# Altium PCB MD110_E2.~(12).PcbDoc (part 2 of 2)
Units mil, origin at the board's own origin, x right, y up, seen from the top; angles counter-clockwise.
Board outline 2320.49 x 1909 mil, 4 copper layers (Top Layer, Signal Layer 1, Signal Layer 2, Bottom Layer), stack 61.2 mil thick; 89 components, 32 nets, 187 pads, 40 vias.
Unrouted connection lines stored in the file: 7.

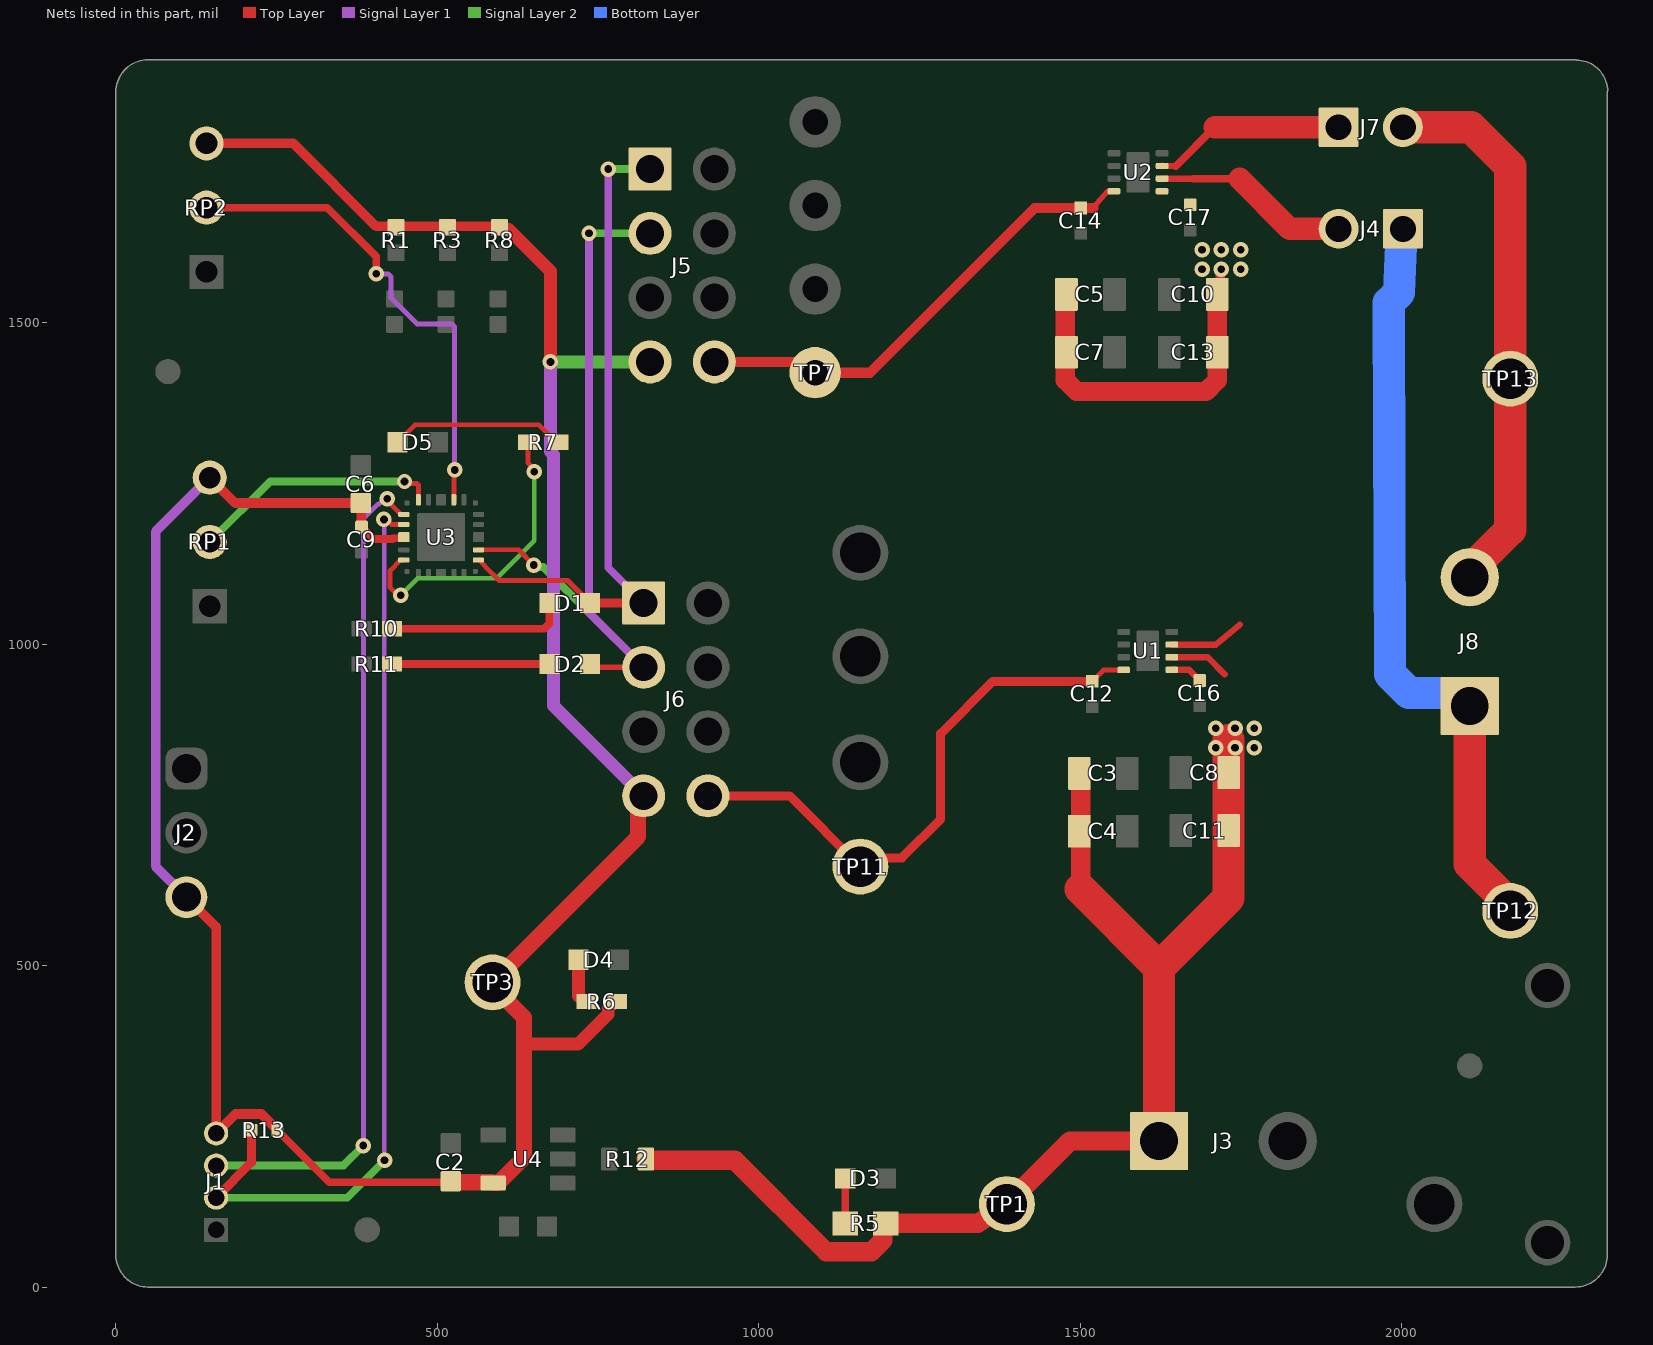
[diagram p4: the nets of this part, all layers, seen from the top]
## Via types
v1: diameter 24, hole 12, Top Layer to Bottom Layer, tented both sides, 36 vias
v2: diameter 19.68, hole 7.87, Top Layer to Bottom Layer, tented both sides, 4 vias

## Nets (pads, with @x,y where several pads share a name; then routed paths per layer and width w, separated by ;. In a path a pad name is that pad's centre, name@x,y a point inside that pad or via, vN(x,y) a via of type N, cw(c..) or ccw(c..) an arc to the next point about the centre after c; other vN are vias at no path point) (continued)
NetD1_1: D1.1 R10.1 | length 279.9
  Top Layer w12: R10.1@429.62,1024 666,1024 674.5,1032.5 D1.1@674.5,1064
NetD2_1: D2.1 R11.1 | length 244.9
  Top Layer w12: R11.1@429.62,969 D2.1@674.5,969
NetD3_2: D3.2 R5.2 | length 70
  Top Layer w12: R5.2@1134.5,99 D3.2@1134.5,169
NetD4_2: D4.2 R6.2 | length 72.6
  Top Layer w20: D4.2@719.5,509 719.5,452.94 728.44,444 R6.2@732.38,444
NetD5_2: D5.2 R7.2 | length 273.3
  Top Layer w7.5: D5.2@438.01,1314 465.38,1341.37 657.63,1341.37 676.25,1322.75 676.25,1322.06 684.31,1314 R7.2@688.24,1314
OUT1: J4.1 J8.1 TP12.1 U1.2 | length 1273.9
  Top Layer w10: U1.2@1642.4,979.65 1698.35,979.65 1724.61,953.39
  Top Layer w50: J8.1@2106,904 2106,658.01 2169,595.01 TP12.1@2169,585
  Bottom Layer w50: J4.1@2000,1638 1996.09,1547.09 1980,1531 1982,953.57 2011.29,924.28 2085.72,924.28 J8.1@2106,904
OUT1_B: J4.2 U2.2 | length 306.9
  Top Layer w10: U2.2@1627.4,1724.16 1676,1724
  Top Layer w12: 1676,1724 1748,1724
  Top Layer w35: 1748,1724 1826,1646 J4.2@1902,1646
OUT2: J7.2 J8.2 TP13.1 U1.3 | length 974.1
  Top Layer w10: U1.3@1642.4,999.34 1711.17,999.34 1748,1030
  Top Layer w50: J7.2@2002,1804 2108,1804 2169,1743 TP13.1@2169,1413 2169,1177.97 2106,1114.97 J8.2@2106,1104
OUT2_B: J7.1 U2.3 | length 299.6
  Top Layer w10: U2.3@1627.4,1743.84 1648.68,1743.69
  Top Layer w12: 1648.68,1743.69 1709,1804
  Top Layer w35: 1709,1804 J7.1@1902,1804
PWM1: D1.2 J5.1 J6.1 U3.13 | length 1050.3
  Top Layer w7.5: U3.13@564.07,1130.97 568.99,1130.97 569.18,1130.78 569.18,1126.38 574.71,1120.85 574.71,1120.33 596.04,1099 702.5,1099
  Top Layer w8: 702.5,1099 D1.2@737.5,1064
  Top Layer w14: D1.2@737.5,1064 J6.1@821,1064
  Signal Layer 1 w12: v1(766,1739) 766,1119 J6.1@821,1064
  Signal Layer 2 w12: v1(766,1739) J5.1@831,1739
PWM2: D2.2 J5.3 J6.3 U3.14 | length 1223.4
  Top Layer w7.5: U3.14@564.07,1146.72 626.28,1146.72 v1(650,1123)
  Top Layer w8: D2.2@737.5,969 742.5,964 J6.3@821,964
  Signal Layer 1 w12: v1(736,1639) 736,1049 J6.3@821,964
  Signal Layer 2 w12: v1(650,1123) 652.94,1120.06 664.94,1120.06 J6.3@821,964 ; v1(736,1639) J5.3@831,1639
SBWTCK: J1.3 U3.1 | length 1304.7
  Top Layer w7.5: v1(422,1226) 422,1222.84 443.01,1201.83 U3.1@447.93,1201.83
  Signal Layer 1 w7.5: v1(385,220) 385,1195.41 407.21,1217.62 409.16,1217.62 417.54,1226 v1(422,1226)
  Signal Layer 2 w12: J1.3@156,189 354,189 v1(385,220)
SBWTDIO: J1.2 R13.2 U3.2 | length 1445.4
  Top Layer w7.5: v1(417,1194) 421.1,1194 429.02,1186.09 U3.2@447.93,1186.09
  Top Layer w14: J1.2@156,139 210.82,193.82 R13.2@210.82,244
  Signal Layer 1 w7.5: v1(417,1194) 417.5,1193.5 417.5,197.5 v1(418,197)
  Signal Layer 2 w12: J1.2@156,139 360,139 v1(418,197)
SPD_REF_1: RP2.2 U3.20 | length 767.6
  Top Layer w7.5: U3.20@525.69,1224.47 525.87,1224.66 525.87,1269.87 v1(527,1271)
  Top Layer w12: RP2.2@141,1679 329,1679 405,1603 v1(405,1576)
  Signal Layer 1 w7.5: v1(405,1576) 423.61,1576 428,1571.61 428,1538.59 468.59,1498 522.61,1498 527,1493.61 v1(527,1271)
SPD_REF_2: RP1.2 U3.23 | length 388.8
  Top Layer w7.5: v1(449,1253) 452.16,1249.84 468.29,1249.84 470.57,1247.57 U3.23@470.57,1224.47
  Signal Layer 2 w12: RP1.2@146,1159 240,1253 v1(449,1253)
STATUS: R7.1 U3.5 | length 476.4
  Top Layer w7.5: v1(443,1076) 438.54,1076 426.54,1088 426.54,1114.5 443.01,1130.97 U3.5@447.93,1130.97 ; R7.1@641,1314 641,1282.34 650.87,1272.46 v1(650.87,1268)
  Signal Layer 2 w7.5: v1(443,1076) 469.62,1102.62 592.69,1102.62 650.87,1160.81 v1(650.87,1268)
VCC: C2.2 C6.2 C9.2 J1.4 J2.3 J5.7 J6.7 R1.2 R3.2 R6.1 R8.2 R13.1 RP1.3 RP2.3 TP3.1 U3.3 U4.5 | length 4508
  Top Layer w12: R13.1@251.18,243.51 254.53,240.16 255.02,240.16 332.14,163.04 C2.2@522.44,163.04 ; C9.2@386.06,1178.38 400.78,1163.65 430.24,1163.65 431.12,1164.53 446.06,1164.53 U3.3@447.93,1166.4
  Top Layer w15: J2.3@109.76,606.48 156,560.24 J1.4@156,239 186.22,269.22 226.45,269.22 251.18,244.49 R13.1@251.18,244 R13.1@251.18,243.51 ; RP2.3@141,1779 276,1779 405,1650 R8.2@593,1650 ; RP1.3@146,1259 185.53,1219.47 C6.2@381,1219.47 381.61,1218.86 381.61,1182.83 C9.2@382.22,1182.22
  Top Layer w20: R8.2@596,1649 599.69,1645.31 610.86,1645.31 676,1580.17 v1(676,1439) ; 635,377.83 719.05,377.83 766,424.79 766,434.32 775.68,444 R6.1@779.62,444
  Top Layer w25: C2.2@522.44,163.04 585.43,163.04 U4.5@586.87,161.6 594.74,161.6 635,201.86 635,377.83 635,419.06 586,468.06 TP3.1@586,474 812.54,700.54 812.54,755.54 J6.7@821,764
  Signal Layer 1 w15: J2.3@109.76,606.48 61.91,654.33 61.91,1174.91 RP1.3@146,1259
  Signal Layer 1 w20: v1(676,1439) 676,1299.44 680.75,1294.69 680.75,904.25 J6.7@821,764
  Signal Layer 2 w20: v1(676,1439) J5.7@831,1439
VCC_DRV: C12.2 J6.8 TP11.1 U1.8 | length 896.8
  Top Layer w8: C12.2@1519,942.18 1536.79,959.97 U1.8@1567.6,959.97
  Top Layer w14: J6.8@921,764 1048,764 TP11.1@1158,654 1171.5,667.5 1222.5,667.5 1283,728 1283,861 1364.18,942.18 C12.2@1519,942.18
VCC_DRV_B: C14.2 J5.8 TP7.1 U2.8 | length 736.7
  Top Layer w8: 1520.33,1678.45 U2.8@1542.76,1704.47
  Top Layer w16: J5.8@931,1439 1057.47,1439 1074.19,1422.28 TP7.1@1087.72,1422.28 1173.04,1422.28 1429.2,1678.45 C14.2@1501,1678.45 1520.33,1678.45
VM: C3.1 C4.1 C5.1 C7.1 C8.1 C10.1 C11.1 C13.1 C16.2 C17.2 J3.1 R5.1 R12.1 TP1.1 U1.1 U2.1 | length 2602.6
  Top Layer w10: U1.1@1642.4,959.97 1669.4,959.97 C16.2@1686,943.37 1686,942.16 1690.84,937.32 1690.84,938.53 C16.2@1686.61,942.76
  Top Layer w15: C10.1@1713.4,1544 1717.88,1548.47 1717.88,1581.62 v1(1719.6,1583.35)
  Top Layer w30: R12.1@824.54,199 826.54,197 963,197 1105,55 1175.24,55 1192.81,72.57 1192.81,95.3 1196.51,99 R5.1@1197.5,99 1340.58,99 TP1.1@1386,129 ; TP1.1@1370.58,129 TP1.1@1386,129 ; C5.1@1478.6,1544 1477,1542.4 1477,1410.57 1494.57,1393 1695.83,1393 1713.4,1410.57 C13.1@1713.4,1454 C10.1@1713.4,1544 ; C3.1@1498.6,799 1501,796.6 1501,619 ; J3.1@1622.81,227.11 1484.11,227.11 TP1.1@1386,129
  Top Layer w50: 1501,619 1622.81,497.19 ; J3.1@1622.81,227.11 1622.81,497.19 ; 1731,851 1731,605.38 1622.81,497.19
  other v1: 1711,839 1741,839 1771,839 1711,869 1741,869 1771,869 1689.6,1583.35 1749.6,1583.35 1689.6,1613.35 1719.6,1613.35 1749.6,1613.35
pads on no net: C14.1 FID1.1 FID2.1 FID3.1 H1.0 H2.0 H3.0 H4.0 SH-J1.0 SH-J2.0 SH-J3.0 SH-J4.0 SH-J5.0 SH-J6.0 SH-J7.0 SH-J8.0 SH-J9.0 SH-J10.0 SH-J11.0 U3. U3.6 U3.7 U3.8 U3.9 U3.10 U3.12 U3.18 U3.19 U3.21 U3.22 U3.24 U4.2

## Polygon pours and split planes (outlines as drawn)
VM on Top Layer "TOP_LAYER_VM_P029" (solid, remove dead copper, pour order 29): 1611.6,1699.35 1611.6,1710 1676.94,1710 1769.6,1617.35 1769.6,1567.35 1683.6,1567.35 1674.6,1576.35 1674.6,1665.35 1645.6,1665.35
VM on Top Layer "TOP_LAYER_VM_P024" (solid, remove dead copper, pour order 24): 1633,955 1633,968 1696,968 1791,873 1791,823 1705,823 1696,832 1696,921 1683,921 1649,955
OUT2 on Top Layer "TOP_LAYER_OUT2_P022" (solid, pour order 22): 2303.5,989.5 2303.5,1256.1 1957,1256.1 1667.75,989.5
OUT1 on Top Layer "TOP_LAYER_OUT1_P021" (solid, pour order 21): 1681.36,987.5 2305,987.5 2305,726.5 1969.91,726.5
GND on Top Layer "TOP_LAYER_GND_P056" (solid, remove dead copper, pour order 30): 1,1909 2321.51,1909 2321.51,-81 1,-81
VM on Bottom Layer "BOTTOM_LAYER_VM_P026" (solid, remove dead copper, pour order 26): 1691,819 1791,819 1791,1619 1781,1629 1671,1629 1671,1569 1691,1549
GND on Bottom Layer "BOTTOM_LAYER_GND_P031" (solid, remove dead copper, pour order 31): 1,1 2321.51,1 2321.51,1909 1,1909
GND on Signal Layer 1 "TOP_LAYER_GND_P056" (solid, remove dead copper, pour order 27): 6.76,1918.32 2327.27,1918.32 2327.27,-71.68 6.76,-71.68
GND on Signal Layer 2 "TOP_LAYER_GND_P056" (solid, remove dead copper, pour order 28): 1,1909 2321.51,1909 2321.51,-81 1,-81

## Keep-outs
Keep-Out Layer:
  text ".Layer_Name" at 574,-1780.49 h25

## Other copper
Top Layer:
  text ".Layer_Name" at 574,-1780.49 h25
Bottom Layer:
  text ".Layer_Name" at 574,-1780.49 h25

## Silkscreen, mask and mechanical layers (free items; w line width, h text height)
Top Overlay:
  circle w10: c426,1249 r5
  lines w8: 24.97,44 326,44 326,279 24.97,279 24.97,44 ; 41,394 446,394 446,914 41,914 41,394 ; 41.2,394.45 446.2,394.45 446.2,554.45 41.2,554.45 41.2,394.45 ; 391.95,1436.85 641.95,1436.85 641.95,1716.85 391.95,1716.85 391.95,1436.85 ; 481,54 856,54 856,314.94 481,314.94 481,54 ; 749.99,1329 2081,1329 2081,1879 749.99,1879 749.99,1329
  lines w10: 1481,874.31 1481,1064.05 1709.27,1062.61 1709.72,873.56 1481,874.31
  lines w15: 908.34,359 1461,359 1461,519 908.34,519 908.34,359
  text "IN1/EN PWM" at 245.21,1852.67 h65 r270
  text "OUT2_B" at 1679,1826.31 h45
  text "OUT2" at 2088,1825.61 h45
  text "Parallel / DRV8218" at 753.21,1799.58 h48
  text "IN1/EN" at 1169.72,1794.67 h55
  text "EVM ID / Resistors" at 389.16,1717.81 h48
  text "IN2/PH" at 1169.72,1669.67 h55
  text "OUT1_B" at 1680,1669.31 h45
  text "OUT1" at 2088,1665.52 h45
  text "ID1" at 408.25,1560.94 h40
  text "ID2" at 491.24,1560.94 h40
  text "ID3" at 572.12,1560.94 h40
  text "MODE" at 1169.72,1534.67 h55
  text "VCC" at 1169.72,1404.65 h55
  text "MCU Status" at 418.62,1354.8 h60
  text "IN2/PH PWM" at 260.21,1332.67 h65 r270
  text "OUT2" at 2079.94,1271.4 h80
  text "IN1/EN" at 1240,1118.21 h65
  text "DRV8218DSG" at 1430.12,1074.8 h60
  text "IN2/PH" at 1240,960.21 h65
  text "MODE" at 1240,794.21 h65
  text "GND" at 177.76,792.28 h60
  text "MODE" at 179.76,680.88 h80
  text "OUT1" at 2078.98,662.4 h80
  text "VCC" at 1240,632.18 h65
  text "VCC" at 174.51,587.25 h60
  text "VCC" at 517.33,558.36 h80
  text "VCC LED" at 704.56,544.77 h60
  text "1.8V - 11V" at 1616,544.05 h50
  text "VM" at 1549.94,473.4 h80
  text "GND" at 1744.6,469.41 h80
  text "GND = PWM / VCC = PH/EN / Hi-Z  = ½ bridge" at 56,392.88 h60
  text "Max VCC: 3.3V" at 488.24,364.8 h60
  text "DRV8218EVM" at 911,359.37 h115
  text "3.3V LDO" at 479.72,318.06 h48
  text "'.PRJ_Number'.PCB_Rev" at 904.48,290.98 h72.83
  text "Programming" at 24.72,279.11 h48
  text "VM" at 1334.94,213.4 h80
  text "GND" at 1980,213.4 h80
  text "VM LED" at 1035.93,204.8 h60
  text "0Ω" at 756.31,111.58 h70
  text ".Layer_Name" at 574,-1780.49 h25
Bottom Overlay:
  text ".Layer_Name" at 574,-1780.49 h25
Top Paste:
  text ".Layer_Name" at 574,-1780.49 h25
Bottom Paste:
  text ".Layer_Name" at 574,-1780.49 h25
Top Solder:
  text ".Layer_Name" at 574,-1780.49 h25
  text ".Layer_Name" at 574,-1780.49 h25
Bottom Solder:
  text ".Layer_Name" at 574,-1780.49 h25
Drill Guide:
  text ".Layer_Name" at 574,-1780.49 h25
M1 Board Outline:
  lines w10: 0,50 ccw(c50,50) 50,0 2270,0 ccw(c2270,50) 2320,50 2320,1860 ; 0,51 0,1859 cw(c50,1859) 50,1909 2272,1909 ; 2270.86,1909 cw(c2270.86,1908.35) 2271.51,1908.35 ; 2272,1908.49 cw(c2272,1860) 2320.49,1860
  text ".Layer_Name" at 574,-1780.49 h25
M2 Board Dimensions:
  rectangle: -3,-1197 122,-1072
  rectangle: 122,-1322 497,-1197
  lines w7: -3,-1197 997,-1197 ; 122,-1322 122,-1072 ; 247,-1322 247,-1072 ; 497,-1322 497,-1072 ; 747,-1322 747,-1072 ; -3,-1322 997,-1322 997,-1072 -3,-1072 -3,-1322
  text ".Layer_Name" at 574,-1780.49 h25
M3 3D STEP Top:
  text ".Layer_Name" at 574,-1780.49 h25
M4 3D STEP Bottom:
  text ".Layer_Name" at 574,-1780.49 h25
M5 Assembly Top:
  lines w10: -295,-1852.17 6305,-1852.17 ; -295,-1648.83 6307,-1648.83 ; -295,-1445.5 -295,-2055.5 3710,-2055.5 6307,-2055.5 6307,-1445.5 -294.5,-1445.5 -294.5,-2055.5 1281,-2055.5 ; 2170,-2055.5 2170,-1445.5 ; 3437,-1648.83 3437,-1445.5 ; 4277,-1648.83 4277,-1445.5 ; 4899,-2062 4899,-1859.17
  text "COMPONENTS MARKED 'DNP' SHOULD NOT BE POPULATED." at 1150.5,-1240.5 h25
  text "ASSEMBLY VARIANT:" at 1150,-1356 h25
  text ".VariantName" at 2186,-1356 h25
  text "PCB VIEWED FROM TOP SIDE" at -231.5,-1577.67 h25
  text "BOARD #:" at 2245,-1577.67 h25
  text ".PRJ_Number" at 2790.5,-1577.67 h25
  text "REV:" at 3635,-1577.67 h25
  text ".PCB_Rev" at 3926.5,-1577.67 h25
  text "SVN REV:" at 4473,-1577.67 h25
  text ".VersionControl_RevNumber" at 4979,-1577.67 h25
  text "TID #:" at 2245,-1781 h25
  text ".TID" at 2790.5,-1781 h25
  text "PLOT NAME =" at -231.5,-1986.34 h25
  text ".plot_File_Name" at 574,-1986.34 h25
  text "GENERATED    :" at 2247,-1986.34 h25
  text ".Print_Date" at 3116.5,-1986.34 h25
  text ".Print_Time" at 3845.5,-1986.34 h25
  text "TEXAS INSTRUMENTS" at 5110,-1986.34 h25
M6 Assembly Bottom:
  lines w10: -295.5,-1649.33 6306.5,-1649.33 ; -293.5,-1852.67 6306.5,-1852.67 ; 1112.5,-2062.5 1112.5,-1859.67 ; 1734.5,-1649.33 1734.5,-1446 ; 2574.5,-1649.33 2574.5,-1446 ; 3841.5,-2056 3841.5,-1446 ; 4730.5,-2056 6306,-2056 6306,-1446 -295.5,-1446 -295.5,-2056 2301.5,-2056 6306.5,-2056 6306.5,-1446
  text "COMPONENTS MARKED 'DNP' SHOULD NOT BE POPULATED." at 6099,-1240 h25
  text ".VariantName" at 5055,-1356 h25
  text "ASSEMBLY VARIANT:" at 6094,-1356 h25
  text ".VersionControl_RevNumber" at 1032.5,-1578.17 h25
  text "SVN REV:" at 1538.5,-1578.17 h25
  text ".PCB_Rev" at 2085,-1578.17 h25
  text "REV:" at 2376.5,-1578.17 h25
  text ".PRJ_Number" at 3221,-1578.17 h25
  text "BOARD #:" at 3766.5,-1578.17 h25
  text "PCB VIEWED FROM BOTTOM SIDE" at 6243,-1578.17 h25
  text ".TID" at 3221,-1781.5 h25
  text "TID #:" at 3766.5,-1781.5 h25
  text "TEXAS INSTRUMENTS" at 901.5,-1986.84 h25
  text ".Print_Time" at 2166,-1986.84 h25
  text ".Print_Date" at 2895,-1986.84 h25
  text "GENERATED    :" at 3764.5,-1986.84 h25
  text ".plot_File_Name" at 5437.5,-1986.84 h25
  text "PLOT NAME =" at 6243,-1986.84 h25
M9 Title Sheet:
  drawing of 57 lines, arcs and shapes, not listed
  text "1" at 736.84,7114.5 h25
  text "2" at 3232.5,7114.5 h25
  text "3" at 5721.84,7114.5 h25
  text "4" at 8228.51,7114.5 h25
  text "5" at 10727.5,7114.5 h25
  text "6" at 13232.5,7114.5 h25
  text "A" at -419.5,5971.5 h25
  text "A" at 14380.5,5971.5 h25
  text "B" at -419.5,3591.5 h25
  text "B" at 14380.5,3591.5 h25
  text "C" at -419.5,1216.5 h25
  text "C" at 14380.5,1216.5 h25
  text "PROJECT TITLE:" at 11340.5,-644.5 h25
  text ".PRJ_Title" at 11390.5,-777.83 h25
  text "DESIGNED FOR:" at 11340.5,-945.5 h25
  text ".PRJ_Customer" at 11390.5,-1085.5 h25
  text "D" at -419.5,-1153.5 h25
  text "D" at 14380.5,-1153.5 h25
  text "FILE NAME:" at 11340.5,-1245.5 h25
  text ".PCB_File_Name_No_Path" at 11390.5,-1365.5 h25
  text "Texas Instruments (TI) and/or its licensors do not warrant the accuracy or completeness of this specification" at 6371,-1527.34 h25
  text "ENGINEER:" at 11340.5,-1535.5 h25
  text "LAYOUT BY:" at 12845.5,-1535.5 h25
  text "or any information contained therein. TI and/or its licensors do not warrant that this design will meet" at 6326.01,-1640 h25
  text ".PRJ_Engineer" at 11390.5,-1690.49 h25
  text ".PCB_Layout" at 12896,-1690.49 h25
  text "the specifications, will be suitable for your application or fit for any particular purpose, or will operate in" at 6326.01,-1752.67 h25
  text ".Layer_Name" at 574,-1780.49 h25
  text "ALTIUM DESIGNER VERSION:" at 12845.5,-1845.5 h25
  text "an implementation. TI and/or its licensors do not warrant that the design is production worthy. You should" at 6326.01,-1865.33 h25
  text "completely validate and test your design implementation to confirm the system functionality for your application." at 6371,-1978 h25
  text ".print_Scale" at 11390.5,-1978.83 h25
  text ".Application_BuildNumber" at 12896,-1978.83 h25
  text "1" at 736.84,-2185.5 h25
  text "2" at 3232.5,-2185.5 h25
  text "3" at 5721.84,-2185.5 h25
  text "4" at 8228.51,-2185.5 h25
  text "5" at 10727.5,-2185.5 h25
  text "6" at 13232.5,-2185.5 h25
M10 Fab Notes:
  drawing of 189 lines, arcs and shapes, not listed
  text "DESIGN INFORMATION" at 12379.02,5434.17 h25
  text "MIN. TRACK WIDTH:" at 11734.46,5302.05 h25
  text "8" at 12830.7,5302.05 h25
  text "MIL" at 12985.46,5302.05 h25
  text "MIN. CLEARANCE:" at 11734.46,5177.92 h25
  text "0.2" at 12770.7,5177.93 h25
  text "mm" at 12985.46,5177.92 h25
  text "MIN. VIA PAD SIZE:" at 11734.46,5053.8 h25
  text "24" at 12800.71,5053.8 h25
  text "MIL" at 12985.46,5053.8 h25
  text "0.05mm (2MIL)" at 12429.46,4923.9 h25
  text "MINIMUM ANNULAR RING" at 11405.23,4915.67 h25
  text "EXTERNAL" at 13137.46,4915.67 h25
  text "PER" at 11605.23,4805.55 h25
  text "IPC-D-275 CLASS 2 LEVEL C" at 11825.23,4805.54 h25
  text "MIL, HOLES" at 13313.46,4705.07 h25
  text "+/-" at 12921,4696.48 h25
  text "+/-" at 13775,4696.48 h25
  text "REGISTRATION TOLERANCES:" at 11405.23,4695.42 h25
  text "METAL" at 12605,4695.42 h25
  text "5" at 13181.2,4695.42 h25
  text "3" at 14014.2,4695.42 h25
  text "MIL" at 14130.46,4695.42 h25
  text "HOLE SIZE TOLERANCE (UNLESS OTHERWISE SPECIFIED):" at 11405.23,4597.1 h25
  text "+/-" at 13775,4594.23 h25
  text "3" at 14014.2,4593.17 h25
  text "MIL" at 14130.46,4593.17 h25
  text "MATERIAL:" at 11330.46,4455.52 h25
  text "FR-4 High Tg" at 12316.9,4327 h25
  text "X" at 12172.46,4319.01 h25
  text "FR-408" at 11751.46,4314.49 h25
  text "OTHER" at 13239.46,4314.49 h25
  text "62 MIL (1.6mm) +/-10%" at 12071.56,4171.46 h25
  text "X" at 11951.46,4169.01 h25
  text "THICKNESS:" at 11405.23,4163.24 h25
  text "OTHER" at 13356.46,4163.24 h25
  text "TOLERANCE:" at 11405.23,4024.92 h25
  text "X" at 12253.46,4024.92 h25
  text "ANSI IPC-6012 TYPE 3 CLASS 2" at 12431.48,4024.92 h25
  text "OTHER +/-" at 12431.46,3880.73 h25
  text "BOW & TWIST:" at 11405.23,3735.54 h25
  text "X" at 12253.46,3735.54 h25
  text "ANSI IPC-6012 TYPE 3 CLASS 2" at 12431.48,3735.54 h25
  text "OTHER +/-" at 12431.46,3588.85 h25
  text "DRILLING:" at 11330.46,3458.23 h25
  text "NC_DRILL FILES" at 13091.46,3353.04 h25
  text "REFERENCE:" at 11405.23,3349.1 h25
  text "X" at 12062.46,3349.01 h25
  text "AS SHOWN" at 12240.46,3349.1 h25
  text "X" at 12963.46,3349.1 h25
  text "OTHER" at 13389.46,3206.85 h25
  text "PTH COPPER THICKNESS:" at 11404.91,3203.32 h25
  text "X" at 12544.14,3203.32 h25
  text "20-30 um" at 12672.14,3203.32 h25
  text "BOARD FINISH:" at 11330.46,3055.73 h25
  text "SILKSCREEN:" at 11485.68,2945.6 h25
  text "X" at 12443.46,2945.6 h25
  text "TOP" at 12560.46,2945.6 h25
  text "X" at 12953.46,2945.6 h25
  text "BOTTOM" at 13071.46,2945.6 h25
  text "SILKSCREEN COLOR:" at 11485.68,2790.41 h25
  text "X" at 12442.46,2790.41 h25
  text "WHITE" at 12560.46,2790.41 h25
  text "OTHER" at 13071.46,2790.41 h25
  text "X" at 12573.46,2646.96 h25
  text "GREEN" at 12691.46,2646.96 h25
  text "OTHER" at 13309.46,2646.96 h25
  text "SOLDER RESIST COLOR:" at 11485.68,2640.1 h25
  text "X" at 12573.46,2492.71 h25
  text "MATTE" at 12691.46,2492.71 h25
  text "SEMI-GLOSS" at 13309,2492.07 h25
  text "IMMERSION GOLD (ENIG)" at 12391.46,2319.94 h25
  text "ENEPIG" at 13729,2312.72 h25
  text "SURFACE FINISH:" at 11330.46,2311.72 h25
  text "X" at 12213.46,2311.72 h25
  text "IMM. TIN/SILVER OR EQUIV" at 11660,2174.4 h25
  text "OTHER" at 13091.46,2170.47 h25
  text "ARRAY/PANEL:" at 11330.46,2015.09 h25
  text "CUT AND TRIM PER M1 BOARD OUTLINE" at 12391.46,2006.87 h25
  text "N.C. ROUTE" at 12391.46,1870.9 h25
  text "X" at 13079.46,1870.9 h25
  text "V. SCORE" at 13257.46,1870.9 h25
  text "CERTIFICATION:" at 11330.46,1741.77 h25
  text "MATERIALS AND WORKMANSHIP FOR ALL PCBS" at 12055.46,1741.77 h25
  text "TO MEET OR EXCEED THE REQUIREMENTS OF:" at 12055.46,1647.71 h25
  text "X" at 11692.97,1519.08 h25
  text "ANSI IPC-A-600F CLASS ->" at 11820.96,1519.08 h25
  text "X" at 13468.97,1519.08 h25
  text "2" at 13578.96,1519.08 h25
  text "1" at 13263.96,1517.58 h25
  text "3" at 13932.96,1517.58 h25
  text "X" at 12504.97,1371.39 h25
  text "RoHS" at 12632.96,1371.39 h25
  text "OTHER" at 13277.36,1371.39 h25
  text "PER ORDER" at 13674.42,1371.39 h25
  text "ALL BOARDS MUST MEET OR EXCEED UL94-V0 REQUIREMENTS." at 11358,1217.57 h25
  text "PCB MUST BEAR THE UL94V-0 UL REGISTERED MATERIAL ID NUMBER" at 11358,1101.5 h25
  text "ADDITIONAL REQUIREMENTS:" at 11330.46,932.08 h25
  text "MICROSECTION:" at 11405.23,824.95 h25
  text "YES" at 12310.96,824.95 h25
  text "REQUIRED" at 13172.46,680.62 h25
  text "BARE BOARD ELEC. TEST:" at 11405.23,677.76 h25
  text "NONE" at 12710.96,677.76 h25
  text "X" at 13054.46,677.76 h25
  text "PER ORDER" at 13764.46,677.76 h25
  text "XX MIL VIAS REQUIRE NON-CONDUCTIVE FILL AND PLANARIZE" at 11573.38,472.82 h25
  text "XX MIL VIAS REQUIRE CONDUCTIVE FILL AND PLANARIZE" at 11581.38,368.84 h25
  text "OUTER XX MIL TRACES REQUIRE 50 OHM SINGLE-ENDED IMPEDANCE" at 11580.39,205.46 h25
  text "LAYER 2 & 3 (INNER LAYERS) XX MIL WIDE, XX MIL SPACE / TRACES REQUIRE 100 OHM DIFFERENTIAL IMPEDANCE" at 11572.39,-30.26 h25
  text ".Layer_Name" at 574,-1780.49 h25
M11 Gerber Information:
  lines w10: -295,-1852.17 6305,-1852.17 ; -295,-1648.83 6307,-1648.83 ; -295,-1445.5 -295,-2055.5 3710,-2055.5 6307,-2055.5 6307,-1445.5 -294.5,-1445.5 -294.5,-2055.5 1281,-2055.5 ; 2170,-2055.5 2170,-1445.5 ; 3437,-1648.83 3437,-1445.5 ; 4277,-1648.83 4277,-1445.5 ; 4899,-2062 4899,-1859.17
  text "ALL ARTWORK VIEWED FROM TOP SIDE" at -231.5,-1577.67 h25
  text "BOARD #:" at 2245,-1577.67 h25
  text ".PRJ_Number" at 2790.5,-1577.67 h25
  text "REV:" at 3635,-1577.67 h25
  text ".PCB_Rev" at 3926.5,-1577.67 h25
  text "SVN REV:" at 4473,-1577.67 h25
  text ".VersionControl_RevNumber" at 4979,-1577.67 h25
  text "LAYER NAME =" at -231.5,-1780.49 h25
  text "TID #:" at 2245,-1781 h25
  text ".TID" at 2790.5,-1781 h25
  text "PLOT NAME =" at -231.5,-1986.34 h25
  text ".plot_File_Name" at 574,-1986.34 h25
  text "GENERATED    :" at 2247,-1986.34 h25
  text ".Print_Date" at 3116.5,-1986.34 h25
  text ".Print_Time" at 3845.5,-1986.34 h25
  text "TEXAS INSTRUMENTS" at 5110,-1986.34 h25
M12 Stackup:
  drawing of 306 lines, arcs and shapes, not listed
  text "Layer" at 9168.67,1067.5 h25
  text "Name" at 9351.13,1067.5 h25
  text "Material" at 9754.36,1067.5 h25
  text "Thickness" at 10124.26,1067.5 h25
  text "Constant" at 10406.69,1067.5 h25
  text "Board Layer Stack" at 10655.8,1067.5 h25
  text "Top Overlay" at 9351.13,1017.5 h25
  text "Top Solder" at 9351.13,967.5 h25
  text "Solder Resist" at 9754.36,967.5 h25
  text "0.40mil" at 10124.26,967.5 h25
  text "3.5" at 10406.69,967.5 h25
  text "1" at 9168.67,917.5 h25
  text "Top Layer" at 9351.13,917.5 h25
  text "2.80mil" at 10124.26,917.5 h25
  text "Dielectric 1" at 9351.13,867.5 h25
  text "FR4 370" at 9754.36,867.5 h25
  text "11.40mil" at 10124.26,867.5 h25
  text "4.2" at 10406.69,867.5 h25
  text "2" at 9168.67,817.5 h25
  text "Signal Layer 1" at 9351.13,817.5 h25
  text "1.40mil" at 10124.26,817.5 h25
  text "Dielectric 2" at 9351.13,767.5 h25
  text "FR4 370" at 9754.36,767.5 h25
  text "30.00mil" at 10124.26,767.5 h25
  text "4.2" at 10406.69,767.5 h25
  text "3" at 9168.67,717.5 h25
  text "Signal Layer 2" at 9351.13,717.5 h25
  text "1.40mil" at 10124.26,717.5 h25
  text "Dielectric 3" at 9351.13,667.5 h25
  text "FR4 370" at 9754.36,667.5 h25
  text "11.40mil" at 10124.26,667.5 h25
  text "4.2" at 10406.69,667.5 h25
  text "4" at 9168.67,617.5 h25
  text "Bottom Layer" at 9351.13,617.5 h25
  text "2.80mil" at 10124.26,617.5 h25
  text "Bottom Solder" at 9351.13,567.5 h25
  text "Solder Resist" at 9754.36,567.5 h25
  text "0.40mil" at 10124.26,567.5 h25
  text "3.5" at 10406.69,567.5 h25
  text "Bottom Overlay" at 9351.13,517.5 h25
  text ".Layer_Name" at 574,-1780.49 h25
M13 Component Bodies Top:
  text ".Layer_Name" at 574,-1780.49 h25
M14 Component Bodies Bottom:
  text ".Layer_Name" at 574,-1780.49 h25
M15 Courtyards Top:
  text ".Layer_Name" at 574,-1780.49 h25
M16 Courtyards Bottom:
  text ".Layer_Name" at 574,-1780.49 h25
Drill Drawing:
  circle w10: c9771.85,322.66 r6.9
  circle w10: c9771.85,322.66 r11.5
  circle w10: c9771.85,-91.29 r11.5
  lines w10: 9760.36,-200.53 9766.1,-200.53 9766.1,-206.28 9777.6,-206.28 9777.6,-200.53 9783.35,-200.53 9783.35,-189.03 9777.6,-189.03 9777.6,-183.28 9766.1,-183.28 9766.1,-189.03 9760.36,-189.03 9760.36,-200.53 ; 9760.36,-154.54 9760.36,-148.79 9766.1,-143.04 9760.36,-137.29 9760.36,-131.54 9766.1,-131.54 9771.85,-137.29 9777.6,-131.54 9783.35,-131.54 9783.35,-137.29 9777.6,-143.04 9783.35,-148.79 9783.35,-154.54 9777.6,-154.54 9771.85,-148.79 9766.1,-154.54 9760.36,-154.54 ; 9760.36,-28.05 9783.35,-28.05 9771.85,-51.05 9760.36,-28.05 ; 9760.36,0.69 9783.35,0.69 9783.35,23.69 9760.36,23.69 9760.36,0.69 ; 9760.36,52.44 9783.35,52.44 9783.35,75.44 9760.36,75.44 9760.36,52.44 ; 9760.36,109.93 9766.1,109.93 9771.85,104.18 9777.6,109.93 9783.35,109.93 9777.6,115.68 9783.35,121.43 9777.6,121.43 9771.85,127.18 9766.1,121.43 9760.36,121.43 9766.1,115.68 9760.36,109.93 ; 9760.36,155.93 9771.85,161.68 9783.35,155.93 9777.6,167.43 9783.35,178.92 9771.85,173.17 9760.36,178.92 9766.1,167.43 9760.36,155.93 ; 9760.36,213.42 9766.1,213.42 9771.85,207.67 9777.6,213.42 9783.35,213.42 9777.6,219.17 9783.35,224.92 9777.6,224.92 9771.85,230.67 9766.1,224.92 9760.36,224.92 9766.1,219.17 9760.36,213.42 ; 9760.36,270.91 9771.85,259.41 9783.35,270.91 9771.85,282.41 9760.36,270.91 ; 9764.95,57.04 9778.75,57.04 9778.75,70.84 9764.95,70.84 9764.95,57.04 ; 9764.95,215.72 9768.4,215.72 9771.85,212.27 9775.3,215.72 9778.75,215.72 9775.3,219.17 9778.75,222.62 9775.3,222.62 9771.85,226.07 9768.4,222.62 9764.95,222.62 9768.4,219.17 9764.95,215.72
  lines w12: 9737.68,-221.8 11082.08,-221.8 ; 9737.68,347.38 11082.08,347.38 ; 9878.24,-273.55 9878.24,399.12 ; 10016.35,-273.55 10016.35,399.12 ; 10281.12,-273.55 10281.12,399.12 ; 10388.93,-273.55 10388.93,399.12 ; 10544.98,-273.55 10544.98,399.12 ; 10846.46,-273.55 10846.46,399.12 ; 9737.68,-273.55 11082.08,-273.55 11082.08,399.12 9737.68,399.12 9737.68,-273.55
  text "Symbol" at 9768.73,362.9 h30
  text "Quantity" at 9893.76,362.9 h30
  text "Finished Hole Size" at 10031.87,362.9 h30
  text "Plated" at 10296.65,362.9 h30
  text "Hole Type" at 10404.45,362.9 h30
  text "Drill Layer Pair" at 10560.51,362.9 h30
  text "Hole Tolerance" at 10861.99,362.9 h30
  text "4" at 9893.76,311.16 h25
  text "7.87mil (0.200mm)" at 10031.87,311.16 h25
  text "PTH" at 10296.65,311.16 h25
  text "Round" at 10404.45,311.16 h25
  text "Top Layer - Bottom Layer" at 10560.51,311.16 h25
  text "36" at 9893.76,259.41 h25
  text "12.00mil (0.305mm)" at 10031.87,259.41 h25
  text "PTH" at 10296.65,259.41 h25
  text "Round" at 10404.45,259.41 h25
  text "Top Layer - Bottom Layer" at 10560.51,259.41 h25
  text "4" at 9893.76,207.67 h25
  text "25.59mil (0.650mm)" at 10031.87,207.67 h25
  text "PTH" at 10296.65,207.67 h25
  text "Round" at 10404.45,207.67 h25
  text "Top Layer - Bottom Layer" at 10560.51,207.67 h25
  text "6" at 9893.76,155.93 h25
  text "33.47mil (0.850mm)" at 10031.87,155.93 h25
  text "PTH" at 10296.65,155.93 h25
  text "Round" at 10404.45,155.93 h25
  text "Top Layer - Bottom Layer" at 10560.51,155.93 h25
  text "4" at 9893.76,104.18 h25
  text "40.00mil (1.016mm)" at 10031.87,104.18 h25
  text "PTH" at 10296.65,104.18 h25
  text "Round" at 10404.45,104.18 h25
  text "Top Layer - Bottom Layer" at 10560.51,104.18 h25
  text "4" at 9893.76,52.44 h25
  text "40.16mil (1.020mm)" at 10031.87,52.44 h25
  text "PTH" at 10296.65,52.44 h25
  text "Round" at 10404.45,52.44 h25
  text "Top Layer - Bottom Layer" at 10560.51,52.44 h25
  text "16" at 9893.76,0.69 h25
  text "43.31mil (1.100mm)" at 10031.87,0.69 h25
  text "PTH" at 10296.65,0.69 h25
  text "Round" at 10404.45,0.69 h25
  text "Top Layer - Bottom Layer" at 10560.51,0.69 h25
  text "3" at 9893.76,-51.05 h25
  text "45.28mil (1.150mm)" at 10031.87,-51.05 h25
  text "PTH" at 10296.65,-51.05 h25
  text "Round" at 10404.45,-51.05 h25
  text "Top Layer - Bottom Layer" at 10560.51,-51.05 h25
  text "2" at 9893.76,-102.79 h25
  text "51.18mil (1.300mm)" at 10031.87,-102.79 h25
  text "PTH" at 10296.65,-102.79 h25
  text "Round" at 10404.45,-102.79 h25
  text "Top Layer - Bottom Layer" at 10560.51,-102.79 h25
  text "4" at 9893.76,-154.54 h25
  text "59.06mil (1.500mm)" at 10031.87,-154.54 h25
  text "PTH" at 10296.65,-154.54 h25
  text "Round" at 10404.45,-154.54 h25
  text "Top Layer - Bottom Layer" at 10560.51,-154.54 h25
  text "9" at 9893.76,-206.28 h25
  text "63.00mil (1.600mm)" at 10031.87,-206.28 h25
  text "PTH" at 10296.65,-206.28 h25
  text "Round" at 10404.45,-206.28 h25
  text "Top Layer - Bottom Layer" at 10560.51,-206.28 h25
  text "92 Total" at 9893.76,-258.03 h25
  text ".Layer_Name" at 574,-1780.49 h25
Mechanical 17:
  text ".Layer_Name" at 574,-1780.49 h25
Mechanical 18:
  text ".Layer_Name" at 574,-1780.49 h25
Mechanical 19:
  text ".Layer_Name" at 574,-1780.49 h25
